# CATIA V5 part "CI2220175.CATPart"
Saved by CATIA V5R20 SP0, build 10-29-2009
Part number: CI2220175
Bounding box of the stored display mesh (mm): x -19 to 19, y -14.158 to 205, z -27.019 to 20.951
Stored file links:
  C:\Users\Raffaele\Desktop\3D X SITO CF\BOLEX\19-INCLINED ASSEMBLY REF_CI\CI2220175.CATPart

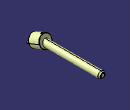
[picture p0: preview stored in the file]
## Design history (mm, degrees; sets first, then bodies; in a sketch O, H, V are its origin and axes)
Set1
  DatumSurface1 to DatumSurface16 "MANIFOLD_SOLID_BREP #389"
  DatumSurface17 to DatumSurface39 "MANIFOLD_SOLID_BREP #1118"
Body1 (main body)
